VERSION 5.7 ;
BUSBITCHARS "[]" ;
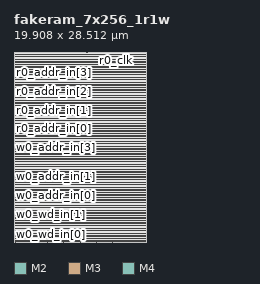
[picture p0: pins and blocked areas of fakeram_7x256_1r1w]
MACRO fakeram_7x256_1r1w
  FOREIGN fakeram_7x256_1r1w 0 0 ;
  SYMMETRY X Y R90 ;
  SIZE 19.908 BY 28.512 ;
  CLASS BLOCK ;
  PIN w0_wd_in[0]
    DIRECTION INPUT ;
    USE SIGNAL ;
    SHAPE ABUTMENT ;
    PORT
      LAYER M2 ;
      RECT 0.000 0.138 0.036 0.150 ;
    END
  END w0_wd_in[0]
  PIN w0_wd_in[1]
    DIRECTION INPUT ;
    USE SIGNAL ;
    SHAPE ABUTMENT ;
    PORT
      LAYER M2 ;
      RECT 0.000 2.946 0.036 2.958 ;
    END
  END w0_wd_in[1]
  PIN w0_wd_in[2]
    DIRECTION INPUT ;
    USE SIGNAL ;
    SHAPE ABUTMENT ;
    PORT
      LAYER M2 ;
      RECT 19.872 0.138 19.908 0.150 ;
    END
  END w0_wd_in[2]
  PIN w0_wd_in[3]
    DIRECTION INPUT ;
    USE SIGNAL ;
    SHAPE ABUTMENT ;
    PORT
      LAYER M2 ;
      RECT 19.872 2.946 19.908 2.958 ;
    END
  END w0_wd_in[3]
  PIN w0_wd_in[4]
    DIRECTION INPUT ;
    USE SIGNAL ;
    SHAPE ABUTMENT ;
    PORT
      LAYER M3 ;
      RECT 0.161 0.000 0.175 0.042 ;
    END
  END w0_wd_in[4]
  PIN w0_wd_in[5]
    DIRECTION INPUT ;
    USE SIGNAL ;
    SHAPE ABUTMENT ;
    PORT
      LAYER M3 ;
      RECT 2.597 0.000 2.611 0.042 ;
    END
  END w0_wd_in[5]
  PIN w0_wd_in[6]
    DIRECTION INPUT ;
    USE SIGNAL ;
    SHAPE ABUTMENT ;
    PORT
      LAYER M3 ;
      RECT 5.033 0.000 5.047 0.042 ;
    END
  END w0_wd_in[6]
  PIN r0_rd_out[0]
    DIRECTION OUTPUT ;
    USE SIGNAL ;
    SHAPE ABUTMENT ;
    PORT
      LAYER M3 ;
      RECT 7.469 0.000 7.483 0.042 ;
    END
  END r0_rd_out[0]
  PIN r0_rd_out[1]
    DIRECTION OUTPUT ;
    USE SIGNAL ;
    SHAPE ABUTMENT ;
    PORT
      LAYER M3 ;
      RECT 9.905 0.000 9.919 0.042 ;
    END
  END r0_rd_out[1]
  PIN r0_rd_out[2]
    DIRECTION OUTPUT ;
    USE SIGNAL ;
    SHAPE ABUTMENT ;
    PORT
      LAYER M3 ;
      RECT 12.341 0.000 12.355 0.042 ;
    END
  END r0_rd_out[2]
  PIN r0_rd_out[3]
    DIRECTION OUTPUT ;
    USE SIGNAL ;
    SHAPE ABUTMENT ;
    PORT
      LAYER M3 ;
      RECT 14.777 0.000 14.791 0.042 ;
    END
  END r0_rd_out[3]
  PIN r0_rd_out[4]
    DIRECTION OUTPUT ;
    USE SIGNAL ;
    SHAPE ABUTMENT ;
    PORT
      LAYER M3 ;
      RECT 0.161 28.470 0.175 28.512 ;
    END
  END r0_rd_out[4]
  PIN r0_rd_out[5]
    DIRECTION OUTPUT ;
    USE SIGNAL ;
    SHAPE ABUTMENT ;
    PORT
      LAYER M3 ;
      RECT 2.317 28.470 2.331 28.512 ;
    END
  END r0_rd_out[5]
  PIN r0_rd_out[6]
    DIRECTION OUTPUT ;
    USE SIGNAL ;
    SHAPE ABUTMENT ;
    PORT
      LAYER M3 ;
      RECT 4.473 28.470 4.487 28.512 ;
    END
  END r0_rd_out[6]
  PIN w0_addr_in[0]
    DIRECTION INPUT ;
    USE SIGNAL ;
    SHAPE ABUTMENT ;
    PORT
      LAYER M2 ;
      RECT 0.000 5.754 0.036 5.766 ;
    END
  END w0_addr_in[0]
  PIN w0_addr_in[1]
    DIRECTION INPUT ;
    USE SIGNAL ;
    SHAPE ABUTMENT ;
    PORT
      LAYER M2 ;
      RECT 0.000 8.562 0.036 8.574 ;
    END
  END w0_addr_in[1]
  PIN w0_addr_in[2]
    DIRECTION INPUT ;
    USE SIGNAL ;
    SHAPE ABUTMENT ;
    PORT
      LAYER M2 ;
      RECT 0.000 11.370 0.036 11.382 ;
    END
  END w0_addr_in[2]
  PIN w0_addr_in[3]
    DIRECTION INPUT ;
    USE SIGNAL ;
    SHAPE ABUTMENT ;
    PORT
      LAYER M2 ;
      RECT 0.000 14.178 0.036 14.190 ;
    END
  END w0_addr_in[3]
  PIN w0_addr_in[4]
    DIRECTION INPUT ;
    USE SIGNAL ;
    SHAPE ABUTMENT ;
    PORT
      LAYER M2 ;
      RECT 19.872 5.754 19.908 5.766 ;
    END
  END w0_addr_in[4]
  PIN w0_addr_in[5]
    DIRECTION INPUT ;
    USE SIGNAL ;
    SHAPE ABUTMENT ;
    PORT
      LAYER M2 ;
      RECT 19.872 8.562 19.908 8.574 ;
    END
  END w0_addr_in[5]
  PIN w0_addr_in[6]
    DIRECTION INPUT ;
    USE SIGNAL ;
    SHAPE ABUTMENT ;
    PORT
      LAYER M2 ;
      RECT 19.872 11.370 19.908 11.382 ;
    END
  END w0_addr_in[6]
  PIN w0_addr_in[7]
    DIRECTION INPUT ;
    USE SIGNAL ;
    SHAPE ABUTMENT ;
    PORT
      LAYER M2 ;
      RECT 19.872 14.178 19.908 14.190 ;
    END
  END w0_addr_in[7]
  PIN r0_addr_in[0]
    DIRECTION INPUT ;
    USE SIGNAL ;
    SHAPE ABUTMENT ;
    PORT
      LAYER M2 ;
      RECT 0.000 16.986 0.036 16.998 ;
    END
  END r0_addr_in[0]
  PIN r0_addr_in[1]
    DIRECTION INPUT ;
    USE SIGNAL ;
    SHAPE ABUTMENT ;
    PORT
      LAYER M2 ;
      RECT 0.000 19.794 0.036 19.806 ;
    END
  END r0_addr_in[1]
  PIN r0_addr_in[2]
    DIRECTION INPUT ;
    USE SIGNAL ;
    SHAPE ABUTMENT ;
    PORT
      LAYER M2 ;
      RECT 0.000 22.602 0.036 22.614 ;
    END
  END r0_addr_in[2]
  PIN r0_addr_in[3]
    DIRECTION INPUT ;
    USE SIGNAL ;
    SHAPE ABUTMENT ;
    PORT
      LAYER M2 ;
      RECT 0.000 25.410 0.036 25.422 ;
    END
  END r0_addr_in[3]
  PIN r0_addr_in[4]
    DIRECTION INPUT ;
    USE SIGNAL ;
    SHAPE ABUTMENT ;
    PORT
      LAYER M2 ;
      RECT 19.872 16.986 19.908 16.998 ;
    END
  END r0_addr_in[4]
  PIN r0_addr_in[5]
    DIRECTION INPUT ;
    USE SIGNAL ;
    SHAPE ABUTMENT ;
    PORT
      LAYER M2 ;
      RECT 19.872 19.794 19.908 19.806 ;
    END
  END r0_addr_in[5]
  PIN r0_addr_in[6]
    DIRECTION INPUT ;
    USE SIGNAL ;
    SHAPE ABUTMENT ;
    PORT
      LAYER M2 ;
      RECT 19.872 22.602 19.908 22.614 ;
    END
  END r0_addr_in[6]
  PIN r0_addr_in[7]
    DIRECTION INPUT ;
    USE SIGNAL ;
    SHAPE ABUTMENT ;
    PORT
      LAYER M2 ;
      RECT 19.872 25.410 19.908 25.422 ;
    END
  END r0_addr_in[7]
  PIN w0_we_in
    DIRECTION INPUT ;
    USE SIGNAL ;
    SHAPE ABUTMENT ;
    PORT
      LAYER M3 ;
      RECT 6.629 28.470 6.643 28.512 ;
    END
  END w0_we_in
  PIN w0_ce_in
    DIRECTION INPUT ;
    USE SIGNAL ;
    SHAPE ABUTMENT ;
    PORT
      LAYER M3 ;
      RECT 8.785 28.470 8.799 28.512 ;
    END
  END w0_ce_in
  PIN w0_clk
    DIRECTION INPUT ;
    USE SIGNAL ;
    SHAPE ABUTMENT ;
    PORT
      LAYER M3 ;
      RECT 10.941 28.470 10.955 28.512 ;
    END
  END w0_clk
  PIN r0_ce_in
    DIRECTION INPUT ;
    USE SIGNAL ;
    SHAPE ABUTMENT ;
    PORT
      LAYER M3 ;
      RECT 13.097 28.470 13.111 28.512 ;
    END
  END r0_ce_in
  PIN r0_clk
    DIRECTION INPUT ;
    USE SIGNAL ;
    SHAPE ABUTMENT ;
    PORT
      LAYER M3 ;
      RECT 15.253 28.470 15.267 28.512 ;
    END
  END r0_clk
  PIN VSS
    DIRECTION INOUT ;
    USE GROUND ;
    PORT
      LAYER M4 ;
      RECT 0.168 0.120 19.740 0.168 ;
      RECT 0.168 0.504 19.740 0.552 ;
      RECT 0.168 0.888 19.740 0.936 ;
      RECT 0.168 1.272 19.740 1.320 ;
      RECT 0.168 1.656 19.740 1.704 ;
      RECT 0.168 2.040 19.740 2.088 ;
      RECT 0.168 2.424 19.740 2.472 ;
      RECT 0.168 2.808 19.740 2.856 ;
      RECT 0.168 3.192 19.740 3.240 ;
      RECT 0.168 3.576 19.740 3.624 ;
      RECT 0.168 3.960 19.740 4.008 ;
      RECT 0.168 4.344 19.740 4.392 ;
      RECT 0.168 4.728 19.740 4.776 ;
      RECT 0.168 5.112 19.740 5.160 ;
      RECT 0.168 5.496 19.740 5.544 ;
      RECT 0.168 5.880 19.740 5.928 ;
      RECT 0.168 6.264 19.740 6.312 ;
      RECT 0.168 6.648 19.740 6.696 ;
      RECT 0.168 7.032 19.740 7.080 ;
      RECT 0.168 7.416 19.740 7.464 ;
      RECT 0.168 7.800 19.740 7.848 ;
      RECT 0.168 8.184 19.740 8.232 ;
      RECT 0.168 8.568 19.740 8.616 ;
      RECT 0.168 8.952 19.740 9.000 ;
      RECT 0.168 9.336 19.740 9.384 ;
      RECT 0.168 9.720 19.740 9.768 ;
      RECT 0.168 10.104 19.740 10.152 ;
      RECT 0.168 10.488 19.740 10.536 ;
      RECT 0.168 10.872 19.740 10.920 ;
      RECT 0.168 11.256 19.740 11.304 ;
      RECT 0.168 11.640 19.740 11.688 ;
      RECT 0.168 12.024 19.740 12.072 ;
      RECT 0.168 12.408 19.740 12.456 ;
      RECT 0.168 12.792 19.740 12.840 ;
      RECT 0.168 13.176 19.740 13.224 ;
      RECT 0.168 13.560 19.740 13.608 ;
      RECT 0.168 13.944 19.740 13.992 ;
      RECT 0.168 14.328 19.740 14.376 ;
      RECT 0.168 14.712 19.740 14.760 ;
      RECT 0.168 15.096 19.740 15.144 ;
      RECT 0.168 15.480 19.740 15.528 ;
      RECT 0.168 15.864 19.740 15.912 ;
      RECT 0.168 16.248 19.740 16.296 ;
      RECT 0.168 16.632 19.740 16.680 ;
      RECT 0.168 17.016 19.740 17.064 ;
      RECT 0.168 17.400 19.740 17.448 ;
      RECT 0.168 17.784 19.740 17.832 ;
      RECT 0.168 18.168 19.740 18.216 ;
      RECT 0.168 18.552 19.740 18.600 ;
      RECT 0.168 18.936 19.740 18.984 ;
      RECT 0.168 19.320 19.740 19.368 ;
      RECT 0.168 19.704 19.740 19.752 ;
      RECT 0.168 20.088 19.740 20.136 ;
      RECT 0.168 20.472 19.740 20.520 ;
      RECT 0.168 20.856 19.740 20.904 ;
      RECT 0.168 21.240 19.740 21.288 ;
      RECT 0.168 21.624 19.740 21.672 ;
      RECT 0.168 22.008 19.740 22.056 ;
      RECT 0.168 22.392 19.740 22.440 ;
      RECT 0.168 22.776 19.740 22.824 ;
      RECT 0.168 23.160 19.740 23.208 ;
      RECT 0.168 23.544 19.740 23.592 ;
      RECT 0.168 23.928 19.740 23.976 ;
      RECT 0.168 24.312 19.740 24.360 ;
      RECT 0.168 24.696 19.740 24.744 ;
      RECT 0.168 25.080 19.740 25.128 ;
      RECT 0.168 25.464 19.740 25.512 ;
      RECT 0.168 25.848 19.740 25.896 ;
      RECT 0.168 26.232 19.740 26.280 ;
      RECT 0.168 26.616 19.740 26.664 ;
      RECT 0.168 27.000 19.740 27.048 ;
      RECT 0.168 27.384 19.740 27.432 ;
      RECT 0.168 27.768 19.740 27.816 ;
      RECT 0.168 28.152 19.740 28.200 ;
    END
  END VSS
  PIN VDD
    DIRECTION INOUT ;
    USE POWER ;
    PORT
      LAYER M4 ;
      RECT 0.168 0.120 19.740 0.168 ;
      RECT 0.168 0.504 19.740 0.552 ;
      RECT 0.168 0.888 19.740 0.936 ;
      RECT 0.168 1.272 19.740 1.320 ;
      RECT 0.168 1.656 19.740 1.704 ;
      RECT 0.168 2.040 19.740 2.088 ;
      RECT 0.168 2.424 19.740 2.472 ;
      RECT 0.168 2.808 19.740 2.856 ;
      RECT 0.168 3.192 19.740 3.240 ;
      RECT 0.168 3.576 19.740 3.624 ;
      RECT 0.168 3.960 19.740 4.008 ;
      RECT 0.168 4.344 19.740 4.392 ;
      RECT 0.168 4.728 19.740 4.776 ;
      RECT 0.168 5.112 19.740 5.160 ;
      RECT 0.168 5.496 19.740 5.544 ;
      RECT 0.168 5.880 19.740 5.928 ;
      RECT 0.168 6.264 19.740 6.312 ;
      RECT 0.168 6.648 19.740 6.696 ;
      RECT 0.168 7.032 19.740 7.080 ;
      RECT 0.168 7.416 19.740 7.464 ;
      RECT 0.168 7.800 19.740 7.848 ;
      RECT 0.168 8.184 19.740 8.232 ;
      RECT 0.168 8.568 19.740 8.616 ;
      RECT 0.168 8.952 19.740 9.000 ;
      RECT 0.168 9.336 19.740 9.384 ;
      RECT 0.168 9.720 19.740 9.768 ;
      RECT 0.168 10.104 19.740 10.152 ;
      RECT 0.168 10.488 19.740 10.536 ;
      RECT 0.168 10.872 19.740 10.920 ;
      RECT 0.168 11.256 19.740 11.304 ;
      RECT 0.168 11.640 19.740 11.688 ;
      RECT 0.168 12.024 19.740 12.072 ;
      RECT 0.168 12.408 19.740 12.456 ;
      RECT 0.168 12.792 19.740 12.840 ;
      RECT 0.168 13.176 19.740 13.224 ;
      RECT 0.168 13.560 19.740 13.608 ;
      RECT 0.168 13.944 19.740 13.992 ;
      RECT 0.168 14.328 19.740 14.376 ;
      RECT 0.168 14.712 19.740 14.760 ;
      RECT 0.168 15.096 19.740 15.144 ;
      RECT 0.168 15.480 19.740 15.528 ;
      RECT 0.168 15.864 19.740 15.912 ;
      RECT 0.168 16.248 19.740 16.296 ;
      RECT 0.168 16.632 19.740 16.680 ;
      RECT 0.168 17.016 19.740 17.064 ;
      RECT 0.168 17.400 19.740 17.448 ;
      RECT 0.168 17.784 19.740 17.832 ;
      RECT 0.168 18.168 19.740 18.216 ;
      RECT 0.168 18.552 19.740 18.600 ;
      RECT 0.168 18.936 19.740 18.984 ;
      RECT 0.168 19.320 19.740 19.368 ;
      RECT 0.168 19.704 19.740 19.752 ;
      RECT 0.168 20.088 19.740 20.136 ;
      RECT 0.168 20.472 19.740 20.520 ;
      RECT 0.168 20.856 19.740 20.904 ;
      RECT 0.168 21.240 19.740 21.288 ;
      RECT 0.168 21.624 19.740 21.672 ;
      RECT 0.168 22.008 19.740 22.056 ;
      RECT 0.168 22.392 19.740 22.440 ;
      RECT 0.168 22.776 19.740 22.824 ;
      RECT 0.168 23.160 19.740 23.208 ;
      RECT 0.168 23.544 19.740 23.592 ;
      RECT 0.168 23.928 19.740 23.976 ;
      RECT 0.168 24.312 19.740 24.360 ;
      RECT 0.168 24.696 19.740 24.744 ;
      RECT 0.168 25.080 19.740 25.128 ;
      RECT 0.168 25.464 19.740 25.512 ;
      RECT 0.168 25.848 19.740 25.896 ;
      RECT 0.168 26.232 19.740 26.280 ;
      RECT 0.168 26.616 19.740 26.664 ;
      RECT 0.168 27.000 19.740 27.048 ;
      RECT 0.168 27.384 19.740 27.432 ;
      RECT 0.168 27.768 19.740 27.816 ;
      RECT 0.168 28.152 19.740 28.200 ;
    END
  END VDD
  OBS
    LAYER M1 ;
    RECT 0 0 19.908 28.512 ;
    LAYER M2 ;
    RECT 0 0 19.908 28.512 ;
    LAYER M3 ;
    RECT 0 0 19.908 28.512 ;
    LAYER M4 ;
    RECT 0 0 19.908 28.512 ;
  END
END fakeram_7x256_1r1w

END LIBRARY
